# Generated by FakeRAM 2.0
VERSION 5.7 ;
BUSBITCHARS "[]" ;
PROPERTYDEFINITIONS
  MACRO width INTEGER ;
  MACRO depth INTEGER ;
  MACRO banks INTEGER ;
END PROPERTYDEFINITIONS
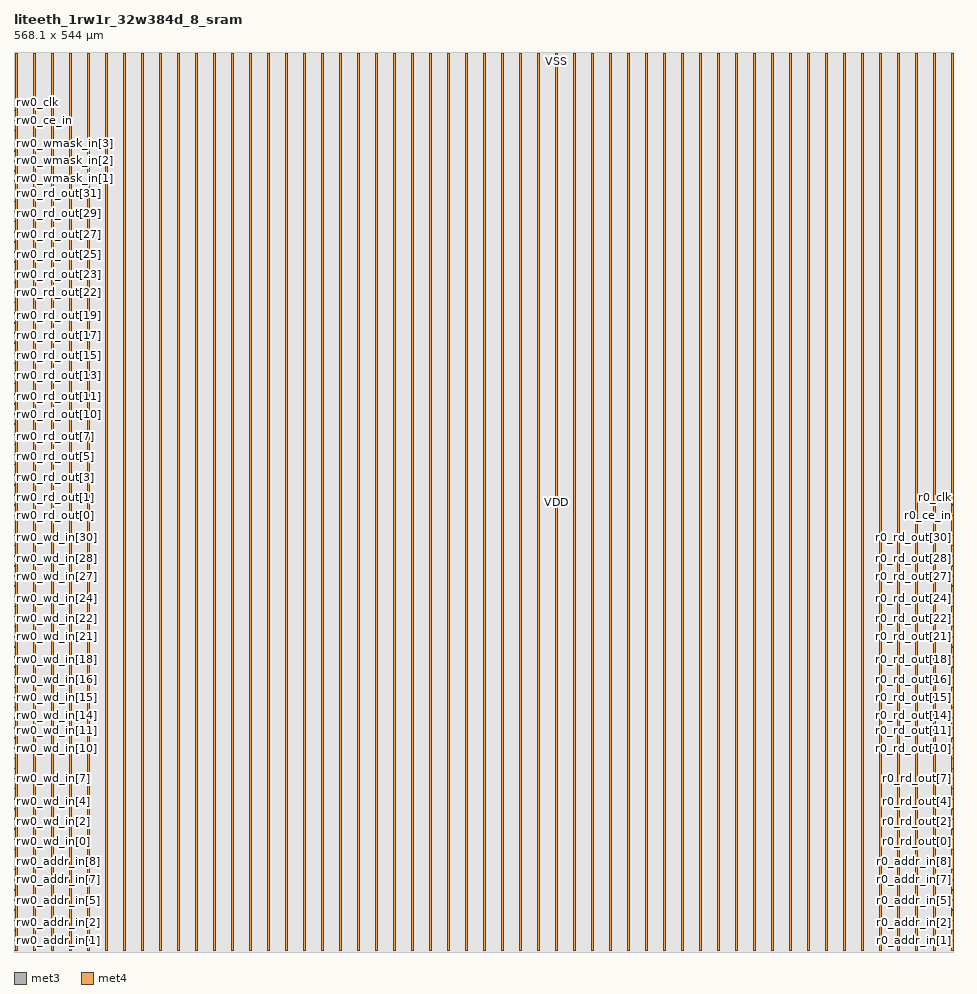
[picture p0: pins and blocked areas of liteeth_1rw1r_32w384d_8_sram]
MACRO liteeth_1rw1r_32w384d_8_sram
  PROPERTY width 32 ;
  PROPERTY depth 384 ;
  PROPERTY banks 1 ;
  FOREIGN liteeth_1rw1r_32w384d_8_sram 0 0 ;
  SYMMETRY X Y R90 ;
  SIZE 568.100 BY 544.000 ;
  CLASS BLOCK ;
  PIN r0_addr_in[0]
    DIRECTION INPUT ;
    USE SIGNAL ;
    SHAPE ABUTMENT ;
    PORT
      LAYER met3 ;
      RECT 567.300 0.680 568.100 0.980 ;
    END
  END r0_addr_in[0]
  PIN r0_addr_in[1]
    DIRECTION INPUT ;
    USE SIGNAL ;
    SHAPE ABUTMENT ;
    PORT
      LAYER met3 ;
      RECT 567.300 6.800 568.100 7.100 ;
    END
  END r0_addr_in[1]
  PIN r0_addr_in[2]
    DIRECTION INPUT ;
    USE SIGNAL ;
    SHAPE ABUTMENT ;
    PORT
      LAYER met3 ;
      RECT 567.300 12.920 568.100 13.220 ;
    END
  END r0_addr_in[2]
  PIN r0_addr_in[3]
    DIRECTION INPUT ;
    USE SIGNAL ;
    SHAPE ABUTMENT ;
    PORT
      LAYER met3 ;
      RECT 567.300 19.040 568.100 19.340 ;
    END
  END r0_addr_in[3]
  PIN r0_addr_in[4]
    DIRECTION INPUT ;
    USE SIGNAL ;
    SHAPE ABUTMENT ;
    PORT
      LAYER met3 ;
      RECT 567.300 25.160 568.100 25.460 ;
    END
  END r0_addr_in[4]
  PIN r0_addr_in[5]
    DIRECTION INPUT ;
    USE SIGNAL ;
    SHAPE ABUTMENT ;
    PORT
      LAYER met3 ;
      RECT 567.300 31.280 568.100 31.580 ;
    END
  END r0_addr_in[5]
  PIN r0_addr_in[6]
    DIRECTION INPUT ;
    USE SIGNAL ;
    SHAPE ABUTMENT ;
    PORT
      LAYER met3 ;
      RECT 567.300 37.400 568.100 37.700 ;
    END
  END r0_addr_in[6]
  PIN r0_addr_in[7]
    DIRECTION INPUT ;
    USE SIGNAL ;
    SHAPE ABUTMENT ;
    PORT
      LAYER met3 ;
      RECT 567.300 43.520 568.100 43.820 ;
    END
  END r0_addr_in[7]
  PIN r0_addr_in[8]
    DIRECTION INPUT ;
    USE SIGNAL ;
    SHAPE ABUTMENT ;
    PORT
      LAYER met3 ;
      RECT 567.300 49.640 568.100 49.940 ;
    END
  END r0_addr_in[8]
  PIN r0_rd_out[0]
    DIRECTION OUTPUT ;
    USE SIGNAL ;
    SHAPE ABUTMENT ;
    PORT
      LAYER met3 ;
      RECT 567.300 61.880 568.100 62.180 ;
    END
  END r0_rd_out[0]
  PIN r0_rd_out[1]
    DIRECTION OUTPUT ;
    USE SIGNAL ;
    SHAPE ABUTMENT ;
    PORT
      LAYER met3 ;
      RECT 567.300 68.000 568.100 68.300 ;
    END
  END r0_rd_out[1]
  PIN r0_rd_out[2]
    DIRECTION OUTPUT ;
    USE SIGNAL ;
    SHAPE ABUTMENT ;
    PORT
      LAYER met3 ;
      RECT 567.300 74.120 568.100 74.420 ;
    END
  END r0_rd_out[2]
  PIN r0_rd_out[3]
    DIRECTION OUTPUT ;
    USE SIGNAL ;
    SHAPE ABUTMENT ;
    PORT
      LAYER met3 ;
      RECT 567.300 80.240 568.100 80.540 ;
    END
  END r0_rd_out[3]
  PIN r0_rd_out[4]
    DIRECTION OUTPUT ;
    USE SIGNAL ;
    SHAPE ABUTMENT ;
    PORT
      LAYER met3 ;
      RECT 567.300 86.360 568.100 86.660 ;
    END
  END r0_rd_out[4]
  PIN r0_rd_out[5]
    DIRECTION OUTPUT ;
    USE SIGNAL ;
    SHAPE ABUTMENT ;
    PORT
      LAYER met3 ;
      RECT 567.300 92.480 568.100 92.780 ;
    END
  END r0_rd_out[5]
  PIN r0_rd_out[6]
    DIRECTION OUTPUT ;
    USE SIGNAL ;
    SHAPE ABUTMENT ;
    PORT
      LAYER met3 ;
      RECT 567.300 98.600 568.100 98.900 ;
    END
  END r0_rd_out[6]
  PIN r0_rd_out[7]
    DIRECTION OUTPUT ;
    USE SIGNAL ;
    SHAPE ABUTMENT ;
    PORT
      LAYER met3 ;
      RECT 567.300 104.720 568.100 105.020 ;
    END
  END r0_rd_out[7]
  PIN r0_rd_out[8]
    DIRECTION OUTPUT ;
    USE SIGNAL ;
    SHAPE ABUTMENT ;
    PORT
      LAYER met3 ;
      RECT 567.300 110.840 568.100 111.140 ;
    END
  END r0_rd_out[8]
  PIN r0_rd_out[9]
    DIRECTION OUTPUT ;
    USE SIGNAL ;
    SHAPE ABUTMENT ;
    PORT
      LAYER met3 ;
      RECT 567.300 116.960 568.100 117.260 ;
    END
  END r0_rd_out[9]
  PIN r0_rd_out[10]
    DIRECTION OUTPUT ;
    USE SIGNAL ;
    SHAPE ABUTMENT ;
    PORT
      LAYER met3 ;
      RECT 567.300 123.080 568.100 123.380 ;
    END
  END r0_rd_out[10]
  PIN r0_rd_out[11]
    DIRECTION OUTPUT ;
    USE SIGNAL ;
    SHAPE ABUTMENT ;
    PORT
      LAYER met3 ;
      RECT 567.300 129.200 568.100 129.500 ;
    END
  END r0_rd_out[11]
  PIN r0_rd_out[12]
    DIRECTION OUTPUT ;
    USE SIGNAL ;
    SHAPE ABUTMENT ;
    PORT
      LAYER met3 ;
      RECT 567.300 135.320 568.100 135.620 ;
    END
  END r0_rd_out[12]
  PIN r0_rd_out[13]
    DIRECTION OUTPUT ;
    USE SIGNAL ;
    SHAPE ABUTMENT ;
    PORT
      LAYER met3 ;
      RECT 567.300 141.440 568.100 141.740 ;
    END
  END r0_rd_out[13]
  PIN r0_rd_out[14]
    DIRECTION OUTPUT ;
    USE SIGNAL ;
    SHAPE ABUTMENT ;
    PORT
      LAYER met3 ;
      RECT 567.300 147.560 568.100 147.860 ;
    END
  END r0_rd_out[14]
  PIN r0_rd_out[15]
    DIRECTION OUTPUT ;
    USE SIGNAL ;
    SHAPE ABUTMENT ;
    PORT
      LAYER met3 ;
      RECT 567.300 153.680 568.100 153.980 ;
    END
  END r0_rd_out[15]
  PIN r0_rd_out[16]
    DIRECTION OUTPUT ;
    USE SIGNAL ;
    SHAPE ABUTMENT ;
    PORT
      LAYER met3 ;
      RECT 567.300 159.800 568.100 160.100 ;
    END
  END r0_rd_out[16]
  PIN r0_rd_out[17]
    DIRECTION OUTPUT ;
    USE SIGNAL ;
    SHAPE ABUTMENT ;
    PORT
      LAYER met3 ;
      RECT 567.300 165.920 568.100 166.220 ;
    END
  END r0_rd_out[17]
  PIN r0_rd_out[18]
    DIRECTION OUTPUT ;
    USE SIGNAL ;
    SHAPE ABUTMENT ;
    PORT
      LAYER met3 ;
      RECT 567.300 172.040 568.100 172.340 ;
    END
  END r0_rd_out[18]
  PIN r0_rd_out[19]
    DIRECTION OUTPUT ;
    USE SIGNAL ;
    SHAPE ABUTMENT ;
    PORT
      LAYER met3 ;
      RECT 567.300 178.160 568.100 178.460 ;
    END
  END r0_rd_out[19]
  PIN r0_rd_out[20]
    DIRECTION OUTPUT ;
    USE SIGNAL ;
    SHAPE ABUTMENT ;
    PORT
      LAYER met3 ;
      RECT 567.300 184.280 568.100 184.580 ;
    END
  END r0_rd_out[20]
  PIN r0_rd_out[21]
    DIRECTION OUTPUT ;
    USE SIGNAL ;
    SHAPE ABUTMENT ;
    PORT
      LAYER met3 ;
      RECT 567.300 190.400 568.100 190.700 ;
    END
  END r0_rd_out[21]
  PIN r0_rd_out[22]
    DIRECTION OUTPUT ;
    USE SIGNAL ;
    SHAPE ABUTMENT ;
    PORT
      LAYER met3 ;
      RECT 567.300 196.520 568.100 196.820 ;
    END
  END r0_rd_out[22]
  PIN r0_rd_out[23]
    DIRECTION OUTPUT ;
    USE SIGNAL ;
    SHAPE ABUTMENT ;
    PORT
      LAYER met3 ;
      RECT 567.300 202.640 568.100 202.940 ;
    END
  END r0_rd_out[23]
  PIN r0_rd_out[24]
    DIRECTION OUTPUT ;
    USE SIGNAL ;
    SHAPE ABUTMENT ;
    PORT
      LAYER met3 ;
      RECT 567.300 208.760 568.100 209.060 ;
    END
  END r0_rd_out[24]
  PIN r0_rd_out[25]
    DIRECTION OUTPUT ;
    USE SIGNAL ;
    SHAPE ABUTMENT ;
    PORT
      LAYER met3 ;
      RECT 567.300 214.880 568.100 215.180 ;
    END
  END r0_rd_out[25]
  PIN r0_rd_out[26]
    DIRECTION OUTPUT ;
    USE SIGNAL ;
    SHAPE ABUTMENT ;
    PORT
      LAYER met3 ;
      RECT 567.300 221.000 568.100 221.300 ;
    END
  END r0_rd_out[26]
  PIN r0_rd_out[27]
    DIRECTION OUTPUT ;
    USE SIGNAL ;
    SHAPE ABUTMENT ;
    PORT
      LAYER met3 ;
      RECT 567.300 227.120 568.100 227.420 ;
    END
  END r0_rd_out[27]
  PIN r0_rd_out[28]
    DIRECTION OUTPUT ;
    USE SIGNAL ;
    SHAPE ABUTMENT ;
    PORT
      LAYER met3 ;
      RECT 567.300 233.240 568.100 233.540 ;
    END
  END r0_rd_out[28]
  PIN r0_rd_out[29]
    DIRECTION OUTPUT ;
    USE SIGNAL ;
    SHAPE ABUTMENT ;
    PORT
      LAYER met3 ;
      RECT 567.300 239.360 568.100 239.660 ;
    END
  END r0_rd_out[29]
  PIN r0_rd_out[30]
    DIRECTION OUTPUT ;
    USE SIGNAL ;
    SHAPE ABUTMENT ;
    PORT
      LAYER met3 ;
      RECT 567.300 245.480 568.100 245.780 ;
    END
  END r0_rd_out[30]
  PIN r0_rd_out[31]
    DIRECTION OUTPUT ;
    USE SIGNAL ;
    SHAPE ABUTMENT ;
    PORT
      LAYER met3 ;
      RECT 567.300 251.600 568.100 251.900 ;
    END
  END r0_rd_out[31]
  PIN r0_ce_in
    DIRECTION INPUT ;
    USE SIGNAL ;
    SHAPE ABUTMENT ;
    PORT
      LAYER met3 ;
      RECT 567.300 263.840 568.100 264.140 ;
    END
  END r0_ce_in
  PIN r0_clk
    DIRECTION INPUT ;
    USE SIGNAL ;
    SHAPE ABUTMENT ;
    PORT
      LAYER met3 ;
      RECT 567.300 269.960 568.100 270.260 ;
    END
  END r0_clk
  PIN rw0_addr_in[0]
    DIRECTION INPUT ;
    USE SIGNAL ;
    SHAPE ABUTMENT ;
    PORT
      LAYER met3 ;
      RECT 0.000 0.680 0.800 0.980 ;
    END
  END rw0_addr_in[0]
  PIN rw0_addr_in[1]
    DIRECTION INPUT ;
    USE SIGNAL ;
    SHAPE ABUTMENT ;
    PORT
      LAYER met3 ;
      RECT 0.000 6.800 0.800 7.100 ;
    END
  END rw0_addr_in[1]
  PIN rw0_addr_in[2]
    DIRECTION INPUT ;
    USE SIGNAL ;
    SHAPE ABUTMENT ;
    PORT
      LAYER met3 ;
      RECT 0.000 12.920 0.800 13.220 ;
    END
  END rw0_addr_in[2]
  PIN rw0_addr_in[3]
    DIRECTION INPUT ;
    USE SIGNAL ;
    SHAPE ABUTMENT ;
    PORT
      LAYER met3 ;
      RECT 0.000 19.040 0.800 19.340 ;
    END
  END rw0_addr_in[3]
  PIN rw0_addr_in[4]
    DIRECTION INPUT ;
    USE SIGNAL ;
    SHAPE ABUTMENT ;
    PORT
      LAYER met3 ;
      RECT 0.000 25.160 0.800 25.460 ;
    END
  END rw0_addr_in[4]
  PIN rw0_addr_in[5]
    DIRECTION INPUT ;
    USE SIGNAL ;
    SHAPE ABUTMENT ;
    PORT
      LAYER met3 ;
      RECT 0.000 31.280 0.800 31.580 ;
    END
  END rw0_addr_in[5]
  PIN rw0_addr_in[6]
    DIRECTION INPUT ;
    USE SIGNAL ;
    SHAPE ABUTMENT ;
    PORT
      LAYER met3 ;
      RECT 0.000 37.400 0.800 37.700 ;
    END
  END rw0_addr_in[6]
  PIN rw0_addr_in[7]
    DIRECTION INPUT ;
    USE SIGNAL ;
    SHAPE ABUTMENT ;
    PORT
      LAYER met3 ;
      RECT 0.000 43.520 0.800 43.820 ;
    END
  END rw0_addr_in[7]
  PIN rw0_addr_in[8]
    DIRECTION INPUT ;
    USE SIGNAL ;
    SHAPE ABUTMENT ;
    PORT
      LAYER met3 ;
      RECT 0.000 49.640 0.800 49.940 ;
    END
  END rw0_addr_in[8]
  PIN rw0_wd_in[0]
    DIRECTION INPUT ;
    USE SIGNAL ;
    SHAPE ABUTMENT ;
    PORT
      LAYER met3 ;
      RECT 0.000 61.880 0.800 62.180 ;
    END
  END rw0_wd_in[0]
  PIN rw0_wd_in[1]
    DIRECTION INPUT ;
    USE SIGNAL ;
    SHAPE ABUTMENT ;
    PORT
      LAYER met3 ;
      RECT 0.000 68.000 0.800 68.300 ;
    END
  END rw0_wd_in[1]
  PIN rw0_wd_in[2]
    DIRECTION INPUT ;
    USE SIGNAL ;
    SHAPE ABUTMENT ;
    PORT
      LAYER met3 ;
      RECT 0.000 74.120 0.800 74.420 ;
    END
  END rw0_wd_in[2]
  PIN rw0_wd_in[3]
    DIRECTION INPUT ;
    USE SIGNAL ;
    SHAPE ABUTMENT ;
    PORT
      LAYER met3 ;
      RECT 0.000 80.240 0.800 80.540 ;
    END
  END rw0_wd_in[3]
  PIN rw0_wd_in[4]
    DIRECTION INPUT ;
    USE SIGNAL ;
    SHAPE ABUTMENT ;
    PORT
      LAYER met3 ;
      RECT 0.000 86.360 0.800 86.660 ;
    END
  END rw0_wd_in[4]
  PIN rw0_wd_in[5]
    DIRECTION INPUT ;
    USE SIGNAL ;
    SHAPE ABUTMENT ;
    PORT
      LAYER met3 ;
      RECT 0.000 92.480 0.800 92.780 ;
    END
  END rw0_wd_in[5]
  PIN rw0_wd_in[6]
    DIRECTION INPUT ;
    USE SIGNAL ;
    SHAPE ABUTMENT ;
    PORT
      LAYER met3 ;
      RECT 0.000 98.600 0.800 98.900 ;
    END
  END rw0_wd_in[6]
  PIN rw0_wd_in[7]
    DIRECTION INPUT ;
    USE SIGNAL ;
    SHAPE ABUTMENT ;
    PORT
      LAYER met3 ;
      RECT 0.000 104.720 0.800 105.020 ;
    END
  END rw0_wd_in[7]
  PIN rw0_wd_in[8]
    DIRECTION INPUT ;
    USE SIGNAL ;
    SHAPE ABUTMENT ;
    PORT
      LAYER met3 ;
      RECT 0.000 110.840 0.800 111.140 ;
    END
  END rw0_wd_in[8]
  PIN rw0_wd_in[9]
    DIRECTION INPUT ;
    USE SIGNAL ;
    SHAPE ABUTMENT ;
    PORT
      LAYER met3 ;
      RECT 0.000 116.960 0.800 117.260 ;
    END
  END rw0_wd_in[9]
  PIN rw0_wd_in[10]
    DIRECTION INPUT ;
    USE SIGNAL ;
    SHAPE ABUTMENT ;
    PORT
      LAYER met3 ;
      RECT 0.000 123.080 0.800 123.380 ;
    END
  END rw0_wd_in[10]
  PIN rw0_wd_in[11]
    DIRECTION INPUT ;
    USE SIGNAL ;
    SHAPE ABUTMENT ;
    PORT
      LAYER met3 ;
      RECT 0.000 129.200 0.800 129.500 ;
    END
  END rw0_wd_in[11]
  PIN rw0_wd_in[12]
    DIRECTION INPUT ;
    USE SIGNAL ;
    SHAPE ABUTMENT ;
    PORT
      LAYER met3 ;
      RECT 0.000 135.320 0.800 135.620 ;
    END
  END rw0_wd_in[12]
  PIN rw0_wd_in[13]
    DIRECTION INPUT ;
    USE SIGNAL ;
    SHAPE ABUTMENT ;
    PORT
      LAYER met3 ;
      RECT 0.000 141.440 0.800 141.740 ;
    END
  END rw0_wd_in[13]
  PIN rw0_wd_in[14]
    DIRECTION INPUT ;
    USE SIGNAL ;
    SHAPE ABUTMENT ;
    PORT
      LAYER met3 ;
      RECT 0.000 147.560 0.800 147.860 ;
    END
  END rw0_wd_in[14]
  PIN rw0_wd_in[15]
    DIRECTION INPUT ;
    USE SIGNAL ;
    SHAPE ABUTMENT ;
    PORT
      LAYER met3 ;
      RECT 0.000 153.680 0.800 153.980 ;
    END
  END rw0_wd_in[15]
  PIN rw0_wd_in[16]
    DIRECTION INPUT ;
    USE SIGNAL ;
    SHAPE ABUTMENT ;
    PORT
      LAYER met3 ;
      RECT 0.000 159.800 0.800 160.100 ;
    END
  END rw0_wd_in[16]
  PIN rw0_wd_in[17]
    DIRECTION INPUT ;
    USE SIGNAL ;
    SHAPE ABUTMENT ;
    PORT
      LAYER met3 ;
      RECT 0.000 165.920 0.800 166.220 ;
    END
  END rw0_wd_in[17]
  PIN rw0_wd_in[18]
    DIRECTION INPUT ;
    USE SIGNAL ;
    SHAPE ABUTMENT ;
    PORT
      LAYER met3 ;
      RECT 0.000 172.040 0.800 172.340 ;
    END
  END rw0_wd_in[18]
  PIN rw0_wd_in[19]
    DIRECTION INPUT ;
    USE SIGNAL ;
    SHAPE ABUTMENT ;
    PORT
      LAYER met3 ;
      RECT 0.000 178.160 0.800 178.460 ;
    END
  END rw0_wd_in[19]
  PIN rw0_wd_in[20]
    DIRECTION INPUT ;
    USE SIGNAL ;
    SHAPE ABUTMENT ;
    PORT
      LAYER met3 ;
      RECT 0.000 184.280 0.800 184.580 ;
    END
  END rw0_wd_in[20]
  PIN rw0_wd_in[21]
    DIRECTION INPUT ;
    USE SIGNAL ;
    SHAPE ABUTMENT ;
    PORT
      LAYER met3 ;
      RECT 0.000 190.400 0.800 190.700 ;
    END
  END rw0_wd_in[21]
  PIN rw0_wd_in[22]
    DIRECTION INPUT ;
    USE SIGNAL ;
    SHAPE ABUTMENT ;
    PORT
      LAYER met3 ;
      RECT 0.000 196.520 0.800 196.820 ;
    END
  END rw0_wd_in[22]
  PIN rw0_wd_in[23]
    DIRECTION INPUT ;
    USE SIGNAL ;
    SHAPE ABUTMENT ;
    PORT
      LAYER met3 ;
      RECT 0.000 202.640 0.800 202.940 ;
    END
  END rw0_wd_in[23]
  PIN rw0_wd_in[24]
    DIRECTION INPUT ;
    USE SIGNAL ;
    SHAPE ABUTMENT ;
    PORT
      LAYER met3 ;
      RECT 0.000 208.760 0.800 209.060 ;
    END
  END rw0_wd_in[24]
  PIN rw0_wd_in[25]
    DIRECTION INPUT ;
    USE SIGNAL ;
    SHAPE ABUTMENT ;
    PORT
      LAYER met3 ;
      RECT 0.000 214.880 0.800 215.180 ;
    END
  END rw0_wd_in[25]
  PIN rw0_wd_in[26]
    DIRECTION INPUT ;
    USE SIGNAL ;
    SHAPE ABUTMENT ;
    PORT
      LAYER met3 ;
      RECT 0.000 221.000 0.800 221.300 ;
    END
  END rw0_wd_in[26]
  PIN rw0_wd_in[27]
    DIRECTION INPUT ;
    USE SIGNAL ;
    SHAPE ABUTMENT ;
    PORT
      LAYER met3 ;
      RECT 0.000 227.120 0.800 227.420 ;
    END
  END rw0_wd_in[27]
  PIN rw0_wd_in[28]
    DIRECTION INPUT ;
    USE SIGNAL ;
    SHAPE ABUTMENT ;
    PORT
      LAYER met3 ;
      RECT 0.000 233.240 0.800 233.540 ;
    END
  END rw0_wd_in[28]
  PIN rw0_wd_in[29]
    DIRECTION INPUT ;
    USE SIGNAL ;
    SHAPE ABUTMENT ;
    PORT
      LAYER met3 ;
      RECT 0.000 239.360 0.800 239.660 ;
    END
  END rw0_wd_in[29]
  PIN rw0_wd_in[30]
    DIRECTION INPUT ;
    USE SIGNAL ;
    SHAPE ABUTMENT ;
    PORT
      LAYER met3 ;
      RECT 0.000 245.480 0.800 245.780 ;
    END
  END rw0_wd_in[30]
  PIN rw0_wd_in[31]
    DIRECTION INPUT ;
    USE SIGNAL ;
    SHAPE ABUTMENT ;
    PORT
      LAYER met3 ;
      RECT 0.000 251.600 0.800 251.900 ;
    END
  END rw0_wd_in[31]
  PIN rw0_rd_out[0]
    DIRECTION OUTPUT ;
    USE SIGNAL ;
    SHAPE ABUTMENT ;
    PORT
      LAYER met3 ;
      RECT 0.000 263.840 0.800 264.140 ;
    END
  END rw0_rd_out[0]
  PIN rw0_rd_out[1]
    DIRECTION OUTPUT ;
    USE SIGNAL ;
    SHAPE ABUTMENT ;
    PORT
      LAYER met3 ;
      RECT 0.000 269.960 0.800 270.260 ;
    END
  END rw0_rd_out[1]
  PIN rw0_rd_out[2]
    DIRECTION OUTPUT ;
    USE SIGNAL ;
    SHAPE ABUTMENT ;
    PORT
      LAYER met3 ;
      RECT 0.000 276.080 0.800 276.380 ;
    END
  END rw0_rd_out[2]
  PIN rw0_rd_out[3]
    DIRECTION OUTPUT ;
    USE SIGNAL ;
    SHAPE ABUTMENT ;
    PORT
      LAYER met3 ;
      RECT 0.000 282.200 0.800 282.500 ;
    END
  END rw0_rd_out[3]
  PIN rw0_rd_out[4]
    DIRECTION OUTPUT ;
    USE SIGNAL ;
    SHAPE ABUTMENT ;
    PORT
      LAYER met3 ;
      RECT 0.000 288.320 0.800 288.620 ;
    END
  END rw0_rd_out[4]
  PIN rw0_rd_out[5]
    DIRECTION OUTPUT ;
    USE SIGNAL ;
    SHAPE ABUTMENT ;
    PORT
      LAYER met3 ;
      RECT 0.000 294.440 0.800 294.740 ;
    END
  END rw0_rd_out[5]
  PIN rw0_rd_out[6]
    DIRECTION OUTPUT ;
    USE SIGNAL ;
    SHAPE ABUTMENT ;
    PORT
      LAYER met3 ;
      RECT 0.000 300.560 0.800 300.860 ;
    END
  END rw0_rd_out[6]
  PIN rw0_rd_out[7]
    DIRECTION OUTPUT ;
    USE SIGNAL ;
    SHAPE ABUTMENT ;
    PORT
      LAYER met3 ;
      RECT 0.000 306.680 0.800 306.980 ;
    END
  END rw0_rd_out[7]
  PIN rw0_rd_out[8]
    DIRECTION OUTPUT ;
    USE SIGNAL ;
    SHAPE ABUTMENT ;
    PORT
      LAYER met3 ;
      RECT 0.000 312.800 0.800 313.100 ;
    END
  END rw0_rd_out[8]
  PIN rw0_rd_out[9]
    DIRECTION OUTPUT ;
    USE SIGNAL ;
    SHAPE ABUTMENT ;
    PORT
      LAYER met3 ;
      RECT 0.000 318.920 0.800 319.220 ;
    END
  END rw0_rd_out[9]
  PIN rw0_rd_out[10]
    DIRECTION OUTPUT ;
    USE SIGNAL ;
    SHAPE ABUTMENT ;
    PORT
      LAYER met3 ;
      RECT 0.000 325.040 0.800 325.340 ;
    END
  END rw0_rd_out[10]
  PIN rw0_rd_out[11]
    DIRECTION OUTPUT ;
    USE SIGNAL ;
    SHAPE ABUTMENT ;
    PORT
      LAYER met3 ;
      RECT 0.000 331.160 0.800 331.460 ;
    END
  END rw0_rd_out[11]
  PIN rw0_rd_out[12]
    DIRECTION OUTPUT ;
    USE SIGNAL ;
    SHAPE ABUTMENT ;
    PORT
      LAYER met3 ;
      RECT 0.000 337.280 0.800 337.580 ;
    END
  END rw0_rd_out[12]
  PIN rw0_rd_out[13]
    DIRECTION OUTPUT ;
    USE SIGNAL ;
    SHAPE ABUTMENT ;
    PORT
      LAYER met3 ;
      RECT 0.000 343.400 0.800 343.700 ;
    END
  END rw0_rd_out[13]
  PIN rw0_rd_out[14]
    DIRECTION OUTPUT ;
    USE SIGNAL ;
    SHAPE ABUTMENT ;
    PORT
      LAYER met3 ;
      RECT 0.000 349.520 0.800 349.820 ;
    END
  END rw0_rd_out[14]
  PIN rw0_rd_out[15]
    DIRECTION OUTPUT ;
    USE SIGNAL ;
    SHAPE ABUTMENT ;
    PORT
      LAYER met3 ;
      RECT 0.000 355.640 0.800 355.940 ;
    END
  END rw0_rd_out[15]
  PIN rw0_rd_out[16]
    DIRECTION OUTPUT ;
    USE SIGNAL ;
    SHAPE ABUTMENT ;
    PORT
      LAYER met3 ;
      RECT 0.000 361.760 0.800 362.060 ;
    END
  END rw0_rd_out[16]
  PIN rw0_rd_out[17]
    DIRECTION OUTPUT ;
    USE SIGNAL ;
    SHAPE ABUTMENT ;
    PORT
      LAYER met3 ;
      RECT 0.000 367.880 0.800 368.180 ;
    END
  END rw0_rd_out[17]
  PIN rw0_rd_out[18]
    DIRECTION OUTPUT ;
    USE SIGNAL ;
    SHAPE ABUTMENT ;
    PORT
      LAYER met3 ;
      RECT 0.000 374.000 0.800 374.300 ;
    END
  END rw0_rd_out[18]
  PIN rw0_rd_out[19]
    DIRECTION OUTPUT ;
    USE SIGNAL ;
    SHAPE ABUTMENT ;
    PORT
      LAYER met3 ;
      RECT 0.000 380.120 0.800 380.420 ;
    END
  END rw0_rd_out[19]
  PIN rw0_rd_out[20]
    DIRECTION OUTPUT ;
    USE SIGNAL ;
    SHAPE ABUTMENT ;
    PORT
      LAYER met3 ;
      RECT 0.000 386.240 0.800 386.540 ;
    END
  END rw0_rd_out[20]
  PIN rw0_rd_out[21]
    DIRECTION OUTPUT ;
    USE SIGNAL ;
    SHAPE ABUTMENT ;
    PORT
      LAYER met3 ;
      RECT 0.000 392.360 0.800 392.660 ;
    END
  END rw0_rd_out[21]
  PIN rw0_rd_out[22]
    DIRECTION OUTPUT ;
    USE SIGNAL ;
    SHAPE ABUTMENT ;
    PORT
      LAYER met3 ;
      RECT 0.000 398.480 0.800 398.780 ;
    END
  END rw0_rd_out[22]
  PIN rw0_rd_out[23]
    DIRECTION OUTPUT ;
    USE SIGNAL ;
    SHAPE ABUTMENT ;
    PORT
      LAYER met3 ;
      RECT 0.000 404.600 0.800 404.900 ;
    END
  END rw0_rd_out[23]
  PIN rw0_rd_out[24]
    DIRECTION OUTPUT ;
    USE SIGNAL ;
    SHAPE ABUTMENT ;
    PORT
      LAYER met3 ;
      RECT 0.000 410.720 0.800 411.020 ;
    END
  END rw0_rd_out[24]
  PIN rw0_rd_out[25]
    DIRECTION OUTPUT ;
    USE SIGNAL ;
    SHAPE ABUTMENT ;
    PORT
      LAYER met3 ;
      RECT 0.000 416.840 0.800 417.140 ;
    END
  END rw0_rd_out[25]
  PIN rw0_rd_out[26]
    DIRECTION OUTPUT ;
    USE SIGNAL ;
    SHAPE ABUTMENT ;
    PORT
      LAYER met3 ;
      RECT 0.000 422.960 0.800 423.260 ;
    END
  END rw0_rd_out[26]
  PIN rw0_rd_out[27]
    DIRECTION OUTPUT ;
    USE SIGNAL ;
    SHAPE ABUTMENT ;
    PORT
      LAYER met3 ;
      RECT 0.000 429.080 0.800 429.380 ;
    END
  END rw0_rd_out[27]
  PIN rw0_rd_out[28]
    DIRECTION OUTPUT ;
    USE SIGNAL ;
    SHAPE ABUTMENT ;
    PORT
      LAYER met3 ;
      RECT 0.000 435.200 0.800 435.500 ;
    END
  END rw0_rd_out[28]
  PIN rw0_rd_out[29]
    DIRECTION OUTPUT ;
    USE SIGNAL ;
    SHAPE ABUTMENT ;
    PORT
      LAYER met3 ;
      RECT 0.000 441.320 0.800 441.620 ;
    END
  END rw0_rd_out[29]
  PIN rw0_rd_out[30]
    DIRECTION OUTPUT ;
    USE SIGNAL ;
    SHAPE ABUTMENT ;
    PORT
      LAYER met3 ;
      RECT 0.000 447.440 0.800 447.740 ;
    END
  END rw0_rd_out[30]
  PIN rw0_rd_out[31]
    DIRECTION OUTPUT ;
    USE SIGNAL ;
    SHAPE ABUTMENT ;
    PORT
      LAYER met3 ;
      RECT 0.000 453.560 0.800 453.860 ;
    END
  END rw0_rd_out[31]
  PIN rw0_wmask_in[0]
    DIRECTION INPUT ;
    USE SIGNAL ;
    SHAPE ABUTMENT ;
    PORT
      LAYER met3 ;
      RECT 0.000 465.800 0.800 466.100 ;
    END
  END rw0_wmask_in[0]
  PIN rw0_wmask_in[1]
    DIRECTION INPUT ;
    USE SIGNAL ;
    SHAPE ABUTMENT ;
    PORT
      LAYER met3 ;
      RECT 0.000 471.920 0.800 472.220 ;
    END
  END rw0_wmask_in[1]
  PIN rw0_wmask_in[2]
    DIRECTION INPUT ;
    USE SIGNAL ;
    SHAPE ABUTMENT ;
    PORT
      LAYER met3 ;
      RECT 0.000 478.040 0.800 478.340 ;
    END
  END rw0_wmask_in[2]
  PIN rw0_wmask_in[3]
    DIRECTION INPUT ;
    USE SIGNAL ;
    SHAPE ABUTMENT ;
    PORT
      LAYER met3 ;
      RECT 0.000 484.160 0.800 484.460 ;
    END
  END rw0_wmask_in[3]
  PIN rw0_we_in
    DIRECTION INPUT ;
    USE SIGNAL ;
    SHAPE ABUTMENT ;
    PORT
      LAYER met3 ;
      RECT 0.000 496.400 0.800 496.700 ;
    END
  END rw0_we_in
  PIN rw0_ce_in
    DIRECTION INPUT ;
    USE SIGNAL ;
    SHAPE ABUTMENT ;
    PORT
      LAYER met3 ;
      RECT 0.000 502.520 0.800 502.820 ;
    END
  END rw0_ce_in
  PIN rw0_clk
    DIRECTION INPUT ;
    USE SIGNAL ;
    SHAPE ABUTMENT ;
    PORT
      LAYER met3 ;
      RECT 0.000 508.640 0.800 508.940 ;
    END
  END rw0_clk
  PIN VSS
    DIRECTION INOUT ;
    USE GROUND ;
    PORT
      LAYER met4 ;
      RECT 1.060 0.680 2.260 543.320 ;
      RECT 11.940 0.680 13.140 543.320 ;
      RECT 22.820 0.680 24.020 543.320 ;
      RECT 33.700 0.680 34.900 543.320 ;
      RECT 44.580 0.680 45.780 543.320 ;
      RECT 55.460 0.680 56.660 543.320 ;
      RECT 66.340 0.680 67.540 543.320 ;
      RECT 77.220 0.680 78.420 543.320 ;
      RECT 88.100 0.680 89.300 543.320 ;
      RECT 98.980 0.680 100.180 543.320 ;
      RECT 109.860 0.680 111.060 543.320 ;
      RECT 120.740 0.680 121.940 543.320 ;
      RECT 131.620 0.680 132.820 543.320 ;
      RECT 142.500 0.680 143.700 543.320 ;
      RECT 153.380 0.680 154.580 543.320 ;
      RECT 164.260 0.680 165.460 543.320 ;
      RECT 175.140 0.680 176.340 543.320 ;
      RECT 186.020 0.680 187.220 543.320 ;
      RECT 196.900 0.680 198.100 543.320 ;
      RECT 207.780 0.680 208.980 543.320 ;
      RECT 218.660 0.680 219.860 543.320 ;
      RECT 229.540 0.680 230.740 543.320 ;
      RECT 240.420 0.680 241.620 543.320 ;
      RECT 251.300 0.680 252.500 543.320 ;
      RECT 262.180 0.680 263.380 543.320 ;
      RECT 273.060 0.680 274.260 543.320 ;
      RECT 283.940 0.680 285.140 543.320 ;
      RECT 294.820 0.680 296.020 543.320 ;
      RECT 305.700 0.680 306.900 543.320 ;
      RECT 316.580 0.680 317.780 543.320 ;
      RECT 327.460 0.680 328.660 543.320 ;
      RECT 338.340 0.680 339.540 543.320 ;
      RECT 349.220 0.680 350.420 543.320 ;
      RECT 360.100 0.680 361.300 543.320 ;
      RECT 370.980 0.680 372.180 543.320 ;
      RECT 381.860 0.680 383.060 543.320 ;
      RECT 392.740 0.680 393.940 543.320 ;
      RECT 403.620 0.680 404.820 543.320 ;
      RECT 414.500 0.680 415.700 543.320 ;
      RECT 425.380 0.680 426.580 543.320 ;
      RECT 436.260 0.680 437.460 543.320 ;
      RECT 447.140 0.680 448.340 543.320 ;
      RECT 458.020 0.680 459.220 543.320 ;
      RECT 468.900 0.680 470.100 543.320 ;
      RECT 479.780 0.680 480.980 543.320 ;
      RECT 490.660 0.680 491.860 543.320 ;
      RECT 501.540 0.680 502.740 543.320 ;
      RECT 512.420 0.680 513.620 543.320 ;
      RECT 523.300 0.680 524.500 543.320 ;
      RECT 534.180 0.680 535.380 543.320 ;
      RECT 545.060 0.680 546.260 543.320 ;
      RECT 555.940 0.680 557.140 543.320 ;
      RECT 566.820 0.680 568.020 543.320 ;
    END
  END VSS
  PIN VDD
    DIRECTION INOUT ;
    USE POWER ;
    PORT
      LAYER met4 ;
      RECT 1.060 0.680 2.260 543.320 ;
      RECT 11.940 0.680 13.140 543.320 ;
      RECT 22.820 0.680 24.020 543.320 ;
      RECT 33.700 0.680 34.900 543.320 ;
      RECT 44.580 0.680 45.780 543.320 ;
      RECT 55.460 0.680 56.660 543.320 ;
      RECT 66.340 0.680 67.540 543.320 ;
      RECT 77.220 0.680 78.420 543.320 ;
      RECT 88.100 0.680 89.300 543.320 ;
      RECT 98.980 0.680 100.180 543.320 ;
      RECT 109.860 0.680 111.060 543.320 ;
      RECT 120.740 0.680 121.940 543.320 ;
      RECT 131.620 0.680 132.820 543.320 ;
      RECT 142.500 0.680 143.700 543.320 ;
      RECT 153.380 0.680 154.580 543.320 ;
      RECT 164.260 0.680 165.460 543.320 ;
      RECT 175.140 0.680 176.340 543.320 ;
      RECT 186.020 0.680 187.220 543.320 ;
      RECT 196.900 0.680 198.100 543.320 ;
      RECT 207.780 0.680 208.980 543.320 ;
      RECT 218.660 0.680 219.860 543.320 ;
      RECT 229.540 0.680 230.740 543.320 ;
      RECT 240.420 0.680 241.620 543.320 ;
      RECT 251.300 0.680 252.500 543.320 ;
      RECT 262.180 0.680 263.380 543.320 ;
      RECT 273.060 0.680 274.260 543.320 ;
      RECT 283.940 0.680 285.140 543.320 ;
      RECT 294.820 0.680 296.020 543.320 ;
      RECT 305.700 0.680 306.900 543.320 ;
      RECT 316.580 0.680 317.780 543.320 ;
      RECT 327.460 0.680 328.660 543.320 ;
      RECT 338.340 0.680 339.540 543.320 ;
      RECT 349.220 0.680 350.420 543.320 ;
      RECT 360.100 0.680 361.300 543.320 ;
      RECT 370.980 0.680 372.180 543.320 ;
      RECT 381.860 0.680 383.060 543.320 ;
      RECT 392.740 0.680 393.940 543.320 ;
      RECT 403.620 0.680 404.820 543.320 ;
      RECT 414.500 0.680 415.700 543.320 ;
      RECT 425.380 0.680 426.580 543.320 ;
      RECT 436.260 0.680 437.460 543.320 ;
      RECT 447.140 0.680 448.340 543.320 ;
      RECT 458.020 0.680 459.220 543.320 ;
      RECT 468.900 0.680 470.100 543.320 ;
      RECT 479.780 0.680 480.980 543.320 ;
      RECT 490.660 0.680 491.860 543.320 ;
      RECT 501.540 0.680 502.740 543.320 ;
      RECT 512.420 0.680 513.620 543.320 ;
      RECT 523.300 0.680 524.500 543.320 ;
      RECT 534.180 0.680 535.380 543.320 ;
      RECT 545.060 0.680 546.260 543.320 ;
      RECT 555.940 0.680 557.140 543.320 ;
      RECT 566.820 0.680 568.020 543.320 ;
    END
  END VDD
  OBS
    LAYER met1 ;
    RECT 0 0 568.100 544.000 ;
    LAYER met2 ;
    RECT 0 0 568.100 544.000 ;
    LAYER met3 ;
    RECT 0 0 568.100 544.000 ;
    LAYER met4 ;
    RECT 0 0 568.100 544.000 ;
    LAYER OVERLAP ;
    RECT 0 0 568.100 544.000 ;
  END
END liteeth_1rw1r_32w384d_8_sram

END LIBRARY
